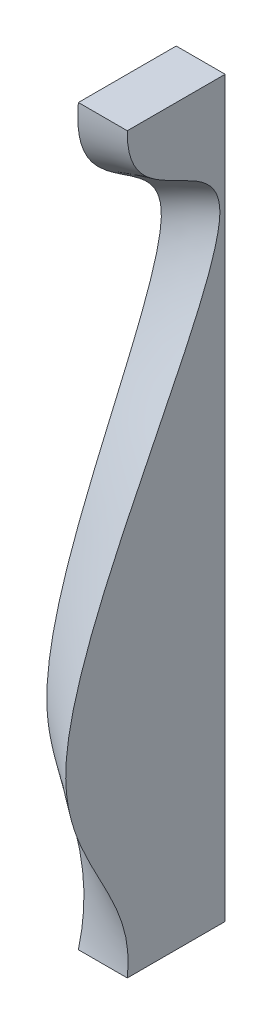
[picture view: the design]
ISO-10303-21;
HEADER;
FILE_DESCRIPTION(('STEP AP214'),'2;1');
FILE_NAME('part.step','',(''),(''),'','','');
FILE_SCHEMA(('AUTOMOTIVE_DESIGN { 1 0 10303 214 1 1 1 1 }'));
ENDSEC;
DATA;
#1=APPLICATION_CONTEXT('core data for automotive mechanical design processes');
#2=APPLICATION_PROTOCOL_DEFINITION('international standard','automotive_design',2000,#1);
#3=PRODUCT_CONTEXT('',#1,'mechanical');
#4=PRODUCT('Part','Part','',(#3));
#5=PRODUCT_RELATED_PRODUCT_CATEGORY('part','',(#4));
#6=PRODUCT_DEFINITION_FORMATION('','',#4);
#7=PRODUCT_DEFINITION_CONTEXT('part definition',#1,'design');
#8=PRODUCT_DEFINITION('design','',#6,#7);
#9=PRODUCT_DEFINITION_SHAPE('','',#8);
#10=(LENGTH_UNIT() NAMED_UNIT(*) SI_UNIT(.MILLI.,.METRE.));
#11=(NAMED_UNIT(*) PLANE_ANGLE_UNIT() SI_UNIT($,.RADIAN.));
#12=(NAMED_UNIT(*) SI_UNIT($,.STERADIAN.) SOLID_ANGLE_UNIT());
#13=UNCERTAINTY_MEASURE_WITH_UNIT(LENGTH_MEASURE(1.E-05),#10,'distance_accuracy_value','');
#14=(GEOMETRIC_REPRESENTATION_CONTEXT(3) GLOBAL_UNCERTAINTY_ASSIGNED_CONTEXT((#13)) GLOBAL_UNIT_ASSIGNED_CONTEXT((#10,
#11,#12)) REPRESENTATION_CONTEXT('',''));
#15=CARTESIAN_POINT('',(0.,0.,0.));
#16=DIRECTION('',(0.,0.,1.));
#17=DIRECTION('',(1.,0.,0.));
#18=AXIS2_PLACEMENT_3D('',#15,#16,#17);
#19=CARTESIAN_POINT('',(-250.,375.,253.120113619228));
#20=DIRECTION('',(1.,0.,0.));
#21=DIRECTION('',(0.,0.,-1.));
#22=AXIS2_PLACEMENT_3D('',#19,#20,#21);
#23=PLANE('',#22);
#24=CARTESIAN_POINT('',(-250.,375.,100.));
#25=CARTESIAN_POINT('',(-250.,374.213593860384,100.016067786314));
#26=CARTESIAN_POINT('',(-250.,373.426981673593,100.023402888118));
#27=CARTESIAN_POINT('',(-250.,371.851176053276,100.019526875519));
#28=CARTESIAN_POINT('',(-250.,371.061982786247,100.008253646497));
#29=CARTESIAN_POINT('',(-250.,369.482255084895,99.9659082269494));
#30=CARTESIAN_POINT('',(-250.,368.691721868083,99.9347894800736));
#31=CARTESIAN_POINT('',(-250.,367.110574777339,99.8514951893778));
#32=CARTESIAN_POINT('',(-250.,366.319962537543,99.7992883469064));
#33=CARTESIAN_POINT('',(-250.,364.739912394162,99.6725782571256));
#34=CARTESIAN_POINT('',(-250.,363.95047583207,99.5980581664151));
#35=CARTESIAN_POINT('',(-250.,362.374033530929,99.4255029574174));
#36=CARTESIAN_POINT('',(-250.,361.587028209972,99.3274640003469));
#37=CARTESIAN_POINT('',(-250.,360.011899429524,99.1060079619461));
#38=CARTESIAN_POINT('',(-250.,359.223796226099,98.9824461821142));
#39=CARTESIAN_POINT('',(-250.,357.652637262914,98.7091560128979));
#40=CARTESIAN_POINT('',(-250.,356.869578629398,98.5594442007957));
#41=CARTESIAN_POINT('',(-250.,355.309788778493,98.2327474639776));
#42=CARTESIAN_POINT('',(-250.,354.533053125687,98.0557837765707));
#43=CARTESIAN_POINT('',(-250.,352.9871734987,97.6735461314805));
#44=CARTESIAN_POINT('',(-250.,352.218024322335,97.4682932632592));
#45=CARTESIAN_POINT('',(-250.,350.688561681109,97.0285245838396));
#46=CARTESIAN_POINT('',(-250.,349.928243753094,96.7940243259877));
#47=CARTESIAN_POINT('',(-250.,348.417663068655,96.2949100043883));
#48=CARTESIAN_POINT('',(-250.,347.667398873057,96.0303003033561));
#49=CARTESIAN_POINT('',(-250.,346.17594428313,95.4694206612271));
#50=CARTESIAN_POINT('',(-250.,345.434792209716,95.1730486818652));
#51=CARTESIAN_POINT('',(-250.,343.965620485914,94.5489680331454));
#52=CARTESIAN_POINT('',(-250.,343.237603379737,94.2212533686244));
#53=CARTESIAN_POINT('',(-250.,341.796482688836,93.5344810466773));
#54=CARTESIAN_POINT('',(-250.,341.083379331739,93.1754229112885));
#55=CARTESIAN_POINT('',(-250.,339.673724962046,92.4262594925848));
#56=CARTESIAN_POINT('',(-250.,338.977172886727,92.0361562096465));
#57=CARTESIAN_POINT('',(-250.,337.605902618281,91.2277573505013));
#58=CARTESIAN_POINT('',(-250.,336.931083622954,90.8096327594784));
#59=CARTESIAN_POINT('',(-250.,335.600448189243,89.9441356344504));
#60=CARTESIAN_POINT('',(-250.,334.944632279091,89.4967622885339));
#61=CARTESIAN_POINT('',(-250.,333.653029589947,88.5739381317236));
#62=CARTESIAN_POINT('',(-250.,333.017243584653,88.0984862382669));
#63=CARTESIAN_POINT('',(-250.,331.766532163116,87.1209777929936));
#64=CARTESIAN_POINT('',(-250.,331.151605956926,86.6189222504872));
#65=CARTESIAN_POINT('',(-250.,329.795982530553,85.4645409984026));
#66=CARTESIAN_POINT('',(-250.,329.061096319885,84.8053794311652));
#67=CARTESIAN_POINT('',(-250.,327.624496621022,83.4516880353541));
#68=CARTESIAN_POINT('',(-250.,326.922789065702,82.7571519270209));
#69=CARTESIAN_POINT('',(-250.,325.552172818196,81.336255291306));
#70=CARTESIAN_POINT('',(-250.,324.883269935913,80.6098891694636));
#71=CARTESIAN_POINT('',(-250.,323.577339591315,79.1289408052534));
#72=CARTESIAN_POINT('',(-250.,322.940316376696,78.3743548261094));
#73=CARTESIAN_POINT('',(-250.,321.693944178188,76.8370718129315));
#74=CARTESIAN_POINT('',(-250.,321.084732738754,76.0542634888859));
#75=CARTESIAN_POINT('',(-250.,319.895088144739,74.4670304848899));
#76=CARTESIAN_POINT('',(-250.,319.314657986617,73.6626035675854));
#77=CARTESIAN_POINT('',(-250.,317.613524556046,71.2219711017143));
#78=CARTESIAN_POINT('',(-250.,316.532611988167,69.5579551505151));
#79=CARTESIAN_POINT('',(-250.,314.552458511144,66.3330919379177));
#80=CARTESIAN_POINT('',(-250.,313.645650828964,64.7768157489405));
#81=CARTESIAN_POINT('',(-250.,311.886408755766,61.633667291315));
#82=CARTESIAN_POINT('',(-250.,311.033983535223,60.0467899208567));
#83=CARTESIAN_POINT('',(-250.,309.366639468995,56.8532032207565));
#84=CARTESIAN_POINT('',(-250.,308.551728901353,55.2464896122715));
#85=CARTESIAN_POINT('',(-250.,306.941347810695,52.0209121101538));
#86=CARTESIAN_POINT('',(-250.,306.145903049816,50.4020354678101));
#87=CARTESIAN_POINT('',(-250.,304.557928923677,47.1634027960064));
#88=CARTESIAN_POINT('',(-250.,303.765398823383,45.5436471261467));
#89=CARTESIAN_POINT('',(-250.,302.564581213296,43.1200179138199));
#90=CARTESIAN_POINT('',(-250.,302.162320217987,42.3131723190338));
#91=CARTESIAN_POINT('',(-250.,301.35129905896,40.7027589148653));
#92=CARTESIAN_POINT('',(-250.,300.942538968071,39.8991910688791));
#93=CARTESIAN_POINT('',(-250.,300.072714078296,38.2129080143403));
#94=CARTESIAN_POINT('',(-250.,299.610650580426,37.3307061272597));
#95=CARTESIAN_POINT('',(-250.,298.671782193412,35.5740706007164));
#96=CARTESIAN_POINT('',(-250.,298.194976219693,34.6996375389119));
#97=CARTESIAN_POINT('',(-250.,297.222756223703,32.9609679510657));
#98=CARTESIAN_POINT('',(-250.,296.727339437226,32.0967329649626));
#99=CARTESIAN_POINT('',(-250.,295.713682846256,30.3810787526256));
#100=CARTESIAN_POINT('',(-250.,295.19543103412,29.5296665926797));
#101=CARTESIAN_POINT('',(-250.,294.13439560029,27.8471510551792));
#102=CARTESIAN_POINT('',(-250.,293.591723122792,27.0159778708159));
#103=CARTESIAN_POINT('',(-250.,292.475678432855,25.3744446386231));
#104=CARTESIAN_POINT('',(-250.,291.902307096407,24.5640839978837));
#105=CARTESIAN_POINT('',(-250.,290.721125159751,22.969581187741));
#106=CARTESIAN_POINT('',(-250.,290.113337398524,22.1854221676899));
#107=CARTESIAN_POINT('',(-250.,288.859407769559,20.6487944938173));
#108=CARTESIAN_POINT('',(-250.,288.213283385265,19.8963116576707));
#109=CARTESIAN_POINT('',(-250.,287.030826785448,18.5958745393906));
#110=CARTESIAN_POINT('',(-250.,286.502890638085,18.0402854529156));
#111=CARTESIAN_POINT('',(-250.,285.420994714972,16.9549699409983));
#112=CARTESIAN_POINT('',(-250.,284.867035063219,16.4252433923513));
#113=CARTESIAN_POINT('',(-250.,283.732500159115,15.3950518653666));
#114=CARTESIAN_POINT('',(-250.,283.151925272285,14.8945864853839));
#115=CARTESIAN_POINT('',(-250.,281.964767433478,13.9267974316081));
#116=CARTESIAN_POINT('',(-250.,281.358213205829,13.4594385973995));
#117=CARTESIAN_POINT('',(-250.,280.119112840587,12.5604108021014));
#118=CARTESIAN_POINT('',(-250.,279.486565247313,12.128743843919));
#119=CARTESIAN_POINT('',(-250.,278.19686599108,11.3039278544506));
#120=CARTESIAN_POINT('',(-250.,277.53971590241,10.9107763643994));
#121=CARTESIAN_POINT('',(-250.,276.199199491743,10.163182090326));
#122=CARTESIAN_POINT('',(-250.,275.51571335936,9.80895400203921));
#123=CARTESIAN_POINT('',(-250.,274.128256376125,9.14304308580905));
#124=CARTESIAN_POINT('',(-250.,273.42428383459,8.83136378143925));
#125=CARTESIAN_POINT('',(-250.,271.99883746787,8.25124842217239));
#126=CARTESIAN_POINT('',(-250.,271.277365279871,7.98280833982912));
#127=CARTESIAN_POINT('',(-250.,269.819489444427,7.48881330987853));
#128=CARTESIAN_POINT('',(-250.,269.083078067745,7.26328122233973));
#129=CARTESIAN_POINT('',(-250.,267.598637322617,6.85432617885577));
#130=CARTESIAN_POINT('',(-250.,266.850607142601,6.67090617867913));
#131=CARTESIAN_POINT('',(-250.,265.34571364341,6.34463144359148));
#132=CARTESIAN_POINT('',(-250.,264.588849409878,6.20178094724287));
#133=CARTESIAN_POINT('',(-250.,263.052791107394,5.95206179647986));
#134=CARTESIAN_POINT('',(-250.,262.273463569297,5.84601911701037));
#135=CARTESIAN_POINT('',(-250.,260.710465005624,5.67173985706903));
#136=CARTESIAN_POINT('',(-250.,259.9267930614,5.60351160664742));
#137=CARTESIAN_POINT('',(-250.,258.356999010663,5.50230729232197));
#138=CARTESIAN_POINT('',(-250.,257.570876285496,5.46934100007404));
#139=CARTESIAN_POINT('',(-250.,255.9980731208,5.43607383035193));
#140=CARTESIAN_POINT('',(-250.,255.211392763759,5.43576884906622));
#141=CARTESIAN_POINT('',(-250.,253.635574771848,5.46537979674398));
#142=CARTESIAN_POINT('',(-250.,252.846439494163,5.49541338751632));
#143=CARTESIAN_POINT('',(-250.,251.269881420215,5.58233007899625));
#144=CARTESIAN_POINT('',(-250.,250.482458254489,5.63920665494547));
#145=CARTESIAN_POINT('',(-250.,248.909704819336,5.77670104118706));
#146=CARTESIAN_POINT('',(-250.,248.12437457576,5.85731914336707));
#147=CARTESIAN_POINT('',(-250.,246.55623892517,6.03966594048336));
#148=CARTESIAN_POINT('',(-250.,245.773433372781,6.14139339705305));
#149=CARTESIAN_POINT('',(-250.,244.104251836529,6.37882046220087));
#150=CARTESIAN_POINT('',(-250.,243.218266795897,6.51725860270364));
#151=CARTESIAN_POINT('',(-250.,241.449902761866,6.81566334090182));
#152=CARTESIAN_POINT('',(-250.,240.567523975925,6.97563115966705));
#153=CARTESIAN_POINT('',(-250.,238.806163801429,7.31477367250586));
#154=CARTESIAN_POINT('',(-250.,237.927183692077,7.49395498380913));
#155=CARTESIAN_POINT('',(-250.,236.172918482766,7.86944897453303));
#156=CARTESIAN_POINT('',(-250.,235.297633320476,8.06576136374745));
#157=CARTESIAN_POINT('',(-250.,233.549648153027,8.47402145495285));
#158=CARTESIAN_POINT('',(-250.,232.676952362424,8.68598715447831));
#159=CARTESIAN_POINT('',(-250.,230.935066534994,9.1238486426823));
#160=CARTESIAN_POINT('',(-250.,230.065876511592,9.34974448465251));
#161=CARTESIAN_POINT('',(-250.,228.329923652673,9.81441706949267));
#162=CARTESIAN_POINT('',(-250.,227.46316455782,10.0532077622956));
#163=CARTESIAN_POINT('',(-250.,225.732893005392,10.5423026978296));
#164=CARTESIAN_POINT('',(-250.,224.86938059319,10.7926071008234));
#165=CARTESIAN_POINT('',(-250.,223.144979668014,11.3038689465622));
#166=CARTESIAN_POINT('',(-250.,222.284092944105,11.5648324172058));
#167=CARTESIAN_POINT('',(-250.,220.565297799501,12.096399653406));
#168=CARTESIAN_POINT('',(-250.,219.707389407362,12.3670035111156));
#169=CARTESIAN_POINT('',(-250.,217.138331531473,13.1919657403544));
#170=CARTESIAN_POINT('',(-250.,215.431434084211,13.7595987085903));
#171=CARTESIAN_POINT('',(-250.,212.017417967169,14.928639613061));
#172=CARTESIAN_POINT('',(-250.,210.310364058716,15.5302357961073));
#173=CARTESIAN_POINT('',(-250.,206.907527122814,16.7590627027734));
#174=CARTESIAN_POINT('',(-250.,205.211734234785,17.3862661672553));
#175=CARTESIAN_POINT('',(-250.,201.829958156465,18.6629462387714));
#176=CARTESIAN_POINT('',(-250.,200.143968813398,19.3124065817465));
#177=CARTESIAN_POINT('',(-250.,196.780557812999,20.630828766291));
#178=CARTESIAN_POINT('',(-250.,195.103132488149,21.2997812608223));
#179=CARTESIAN_POINT('',(-250.,192.592519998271,22.3161454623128));
#180=CARTESIAN_POINT('',(-250.,191.756686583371,22.6570408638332));
#181=CARTESIAN_POINT('',(-250.,190.086694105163,23.3429119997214));
#182=CARTESIAN_POINT('',(-250.,189.252535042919,23.687887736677));
#183=CARTESIAN_POINT('',(-250.,187.58592056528,24.3816247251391));
#184=CARTESIAN_POINT('',(-250.,186.753464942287,24.7303854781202));
#185=CARTESIAN_POINT('',(-250.,185.090074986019,25.4315073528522));
#186=CARTESIAN_POINT('',(-250.,184.259140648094,25.7838684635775));
#187=CARTESIAN_POINT('',(-250.,181.797675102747,26.8335904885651));
#188=CARTESIAN_POINT('',(-250.,180.169207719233,27.5357954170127));
#189=CARTESIAN_POINT('',(-250.,176.917326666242,28.9518221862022));
#190=CARTESIAN_POINT('',(-250.,175.293913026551,29.6656440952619));
#191=CARTESIAN_POINT('',(-250.,172.051586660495,31.1036699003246));
#192=CARTESIAN_POINT('',(-250.,170.432674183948,31.8278743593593));
#193=CARTESIAN_POINT('',(-250.,167.199006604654,33.2855104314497));
#194=CARTESIAN_POINT('',(-250.,165.58425151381,34.0189420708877));
#195=CARTESIAN_POINT('',(-250.,160.745401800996,36.2316499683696));
#196=CARTESIAN_POINT('',(-250.,157.526936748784,37.7232439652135));
#197=CARTESIAN_POINT('',(-250.,151.102189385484,40.7324582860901));
#198=CARTESIAN_POINT('',(-250.,147.895907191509,42.2500788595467));
#199=CARTESIAN_POINT('',(-250.,141.489736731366,45.3074006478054));
#200=CARTESIAN_POINT('',(-250.,138.289858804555,46.8471235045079));
#201=CARTESIAN_POINT('',(-250.,131.897940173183,49.9422902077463));
#202=CARTESIAN_POINT('',(-250.,128.705899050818,51.4977331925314));
#203=CARTESIAN_POINT('',(-250.,122.327650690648,54.6203474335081));
#204=CARTESIAN_POINT('',(-250.,119.141443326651,56.1875184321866));
#205=CARTESIAN_POINT('',(-250.,112.773091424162,59.3300653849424));
#206=CARTESIAN_POINT('',(-250.,109.590946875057,60.9054413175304));
#207=CARTESIAN_POINT('',(-250.,103.226673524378,64.0624449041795));
#208=CARTESIAN_POINT('',(-250.,100.044546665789,65.6440764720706));
#209=CARTESIAN_POINT('',(-250.,93.6813167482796,68.8094607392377));
#210=CARTESIAN_POINT('',(-250.,90.5002136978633,70.3932134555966));
#211=CARTESIAN_POINT('',(-250.,84.137680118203,73.5601113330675));
#212=CARTESIAN_POINT('',(-250.,80.9562495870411,75.1432564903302));
#213=CARTESIAN_POINT('',(-250.,74.5917780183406,78.3063460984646));
#214=CARTESIAN_POINT('',(-250.,71.4087369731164,79.8862905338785));
#215=CARTESIAN_POINT('',(-250.,63.9929354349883,83.5589264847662));
#216=CARTESIAN_POINT('',(-250.,59.75908987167,85.6494296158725));
#217=CARTESIAN_POINT('',(-250.,51.2836060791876,89.8145359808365));
#218=CARTESIAN_POINT('',(-250.,47.0419678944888,91.8891393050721));
#219=CARTESIAN_POINT('',(-250.,38.5481354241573,96.0166037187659));
#220=CARTESIAN_POINT('',(-250.,34.2959411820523,98.069464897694));
#221=CARTESIAN_POINT('',(-250.,25.7811124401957,102.146001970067));
#222=CARTESIAN_POINT('',(-250.,21.518486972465,104.169696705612));
#223=CARTESIAN_POINT('',(-250.,12.977108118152,108.182886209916));
#224=CARTESIAN_POINT('',(-250.,8.69835461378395,110.172380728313));
#225=CARTESIAN_POINT('',(-250.,0.121736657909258,114.11019478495));
#226=CARTESIAN_POINT('',(-250.,-4.17612843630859,116.058512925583));
#227=CARTESIAN_POINT('',(-250.,-12.7913387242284,119.904971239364));
#228=CARTESIAN_POINT('',(-250.,-17.1086713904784,121.803139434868));
#229=CARTESIAN_POINT('',(-250.,-25.7682883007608,125.54155376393));
#230=CARTESIAN_POINT('',(-250.,-30.1105718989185,127.381801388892));
#231=CARTESIAN_POINT('',(-250.,-36.645057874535,130.090936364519));
#232=CARTESIAN_POINT('',(-250.,-38.8266667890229,130.985416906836));
#233=CARTESIAN_POINT('',(-250.,-43.1973848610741,132.755848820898));
#234=CARTESIAN_POINT('',(-250.,-45.3864939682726,133.631800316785));
#235=CARTESIAN_POINT('',(-250.,-48.9765989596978,135.049287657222));
#236=CARTESIAN_POINT('',(-250.,-50.3752376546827,135.596798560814));
#237=CARTESIAN_POINT('',(-250.,-53.1758494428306,136.683213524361));
#238=CARTESIAN_POINT('',(-250.,-54.5778225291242,137.222117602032));
#239=CARTESIAN_POINT('',(-250.,-58.7891943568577,138.825333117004));
#240=CARTESIAN_POINT('',(-250.,-61.6037892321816,139.876046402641));
#241=CARTESIAN_POINT('',(-250.,-67.2479573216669,141.937175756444));
#242=CARTESIAN_POINT('',(-250.,-70.0775316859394,142.947588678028));
#243=CARTESIAN_POINT('',(-250.,-75.752753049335,144.923464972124));
#244=CARTESIAN_POINT('',(-250.,-78.5984019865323,145.888922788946));
#245=CARTESIAN_POINT('',(-250.,-84.3070787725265,147.769605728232));
#246=CARTESIAN_POINT('',(-250.,-87.1701108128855,148.68481815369));
#247=CARTESIAN_POINT('',(-250.,-92.9060745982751,150.456145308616));
#248=CARTESIAN_POINT('',(-250.,-95.7789594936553,151.312411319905));
#249=CARTESIAN_POINT('',(-250.,-101.543128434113,152.961337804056));
#250=CARTESIAN_POINT('',(-250.,-104.434413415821,153.753995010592));
#251=CARTESIAN_POINT('',(-250.,-110.235452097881,155.267085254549));
#252=CARTESIAN_POINT('',(-250.,-113.14520272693,155.987529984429));
#253=CARTESIAN_POINT('',(-250.,-117.523923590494,157.006492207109));
#254=CARTESIAN_POINT('',(-250.,-118.985757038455,157.335843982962));
#255=CARTESIAN_POINT('',(-250.,-121.914209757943,157.972551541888));
#256=CARTESIAN_POINT('',(-250.,-123.380828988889,158.279907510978));
#257=CARTESIAN_POINT('',(-250.,-126.319056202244,158.871110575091));
#258=CARTESIAN_POINT('',(-250.,-127.790664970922,159.154953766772));
#259=CARTESIAN_POINT('',(-250.,-130.738595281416,159.697363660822));
#260=CARTESIAN_POINT('',(-250.,-132.214916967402,159.955929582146));
#261=CARTESIAN_POINT('',(-250.,-134.905530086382,160.401720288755));
#262=CARTESIAN_POINT('',(-250.,-136.119083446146,160.593403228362));
#263=CARTESIAN_POINT('',(-250.,-138.549114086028,160.957369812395));
#264=CARTESIAN_POINT('',(-250.,-139.765591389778,161.129653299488));
#265=CARTESIAN_POINT('',(-250.,-142.201383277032,161.453602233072));
#266=CARTESIAN_POINT('',(-250.,-143.420698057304,161.605266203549));
#267=CARTESIAN_POINT('',(-250.,-145.861864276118,161.886630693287));
#268=CARTESIAN_POINT('',(-250.,-147.083715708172,162.016331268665));
#269=CARTESIAN_POINT('',(-250.,-149.529041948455,162.252264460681));
#270=CARTESIAN_POINT('',(-250.,-150.75251556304,162.358509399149));
#271=CARTESIAN_POINT('',(-250.,-153.201390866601,162.546063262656));
#272=CARTESIAN_POINT('',(-250.,-154.426792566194,162.627372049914));
#273=CARTESIAN_POINT('',(-250.,-156.878901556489,162.763338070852));
#274=CARTESIAN_POINT('',(-250.,-158.105608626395,162.817999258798));
#275=CARTESIAN_POINT('',(-250.,-160.559940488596,162.89891866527));
#276=CARTESIAN_POINT('',(-250.,-161.787565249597,162.925177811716));
#277=CARTESIAN_POINT('',(-250.,-163.571207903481,162.942530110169));
#278=CARTESIAN_POINT('',(-250.,-164.127135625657,162.945003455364));
#279=CARTESIAN_POINT('',(-250.,-165.238980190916,162.944061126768));
#280=CARTESIAN_POINT('',(-250.,-165.79489703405,162.940645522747));
#281=CARTESIAN_POINT('',(-250.,-167.462524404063,162.921546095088));
#282=CARTESIAN_POINT('',(-250.,-168.574145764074,162.897009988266));
#283=CARTESIAN_POINT('',(-250.,-170.796996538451,162.824279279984));
#284=CARTESIAN_POINT('',(-250.,-171.908225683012,162.776076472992));
#285=CARTESIAN_POINT('',(-250.,-174.129398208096,162.656090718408));
#286=CARTESIAN_POINT('',(-250.,-175.239341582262,162.584307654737));
#287=CARTESIAN_POINT('',(-250.,-178.566802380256,162.33371239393));
#288=CARTESIAN_POINT('',(-250.,-180.781772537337,162.11965997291));
#289=CARTESIAN_POINT('',(-250.,-185.200444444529,161.598460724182));
#290=CARTESIAN_POINT('',(-250.,-187.404147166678,161.29132206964));
#291=CARTESIAN_POINT('',(-250.,-191.798597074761,160.585832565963));
#292=CARTESIAN_POINT('',(-250.,-193.989333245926,160.187413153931));
#293=CARTESIAN_POINT('',(-250.,-198.352815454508,159.302851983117));
#294=CARTESIAN_POINT('',(-250.,-200.525562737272,158.816716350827));
#295=CARTESIAN_POINT('',(-250.,-204.850690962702,157.761108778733));
#296=CARTESIAN_POINT('',(-250.,-207.003071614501,157.191635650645));
#297=CARTESIAN_POINT('',(-250.,-211.285362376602,155.974741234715));
#298=CARTESIAN_POINT('',(-250.,-213.415275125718,155.327329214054));
#299=CARTESIAN_POINT('',(-250.,-217.177215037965,154.113688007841));
#300=CARTESIAN_POINT('',(-250.,-218.813885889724,153.56176398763));
#301=CARTESIAN_POINT('',(-250.,-222.073138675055,152.417646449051));
#302=CARTESIAN_POINT('',(-250.,-223.695720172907,151.825451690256));
#303=CARTESIAN_POINT('',(-250.,-226.927054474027,150.603945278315));
#304=CARTESIAN_POINT('',(-250.,-228.535805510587,149.974628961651));
#305=CARTESIAN_POINT('',(-250.,-231.739732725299,148.68225245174));
#306=CARTESIAN_POINT('',(-250.,-233.334908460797,148.019191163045));
#307=CARTESIAN_POINT('',(-250.,-236.512352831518,146.662729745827));
#308=CARTESIAN_POINT('',(-250.,-238.094620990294,145.969328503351));
#309=CARTESIAN_POINT('',(-250.,-241.247136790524,144.555665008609));
#310=CARTESIAN_POINT('',(-250.,-242.817384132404,143.83540208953));
#311=CARTESIAN_POINT('',(-250.,-245.95298615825,142.368728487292));
#312=CARTESIAN_POINT('',(-250.,-247.518298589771,141.62222764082));
#313=CARTESIAN_POINT('',(-250.,-250.639278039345,140.109318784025));
#314=CARTESIAN_POINT('',(-250.,-252.194944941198,139.342910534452));
#315=CARTESIAN_POINT('',(-250.,-255.297868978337,137.79399053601));
#316=CARTESIAN_POINT('',(-250.,-256.845127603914,137.011481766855));
#317=CARTESIAN_POINT('',(-250.,-259.933229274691,135.433933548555));
#318=CARTESIAN_POINT('',(-250.,-261.474072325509,134.638894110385));
#319=CARTESIAN_POINT('',(-250.,-264.551186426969,133.040072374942));
#320=CARTESIAN_POINT('',(-250.,-266.087457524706,132.236290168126));
#321=CARTESIAN_POINT('',(-250.,-269.157435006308,130.623853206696));
#322=CARTESIAN_POINT('',(-250.,-270.69114139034,129.815198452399));
#323=CARTESIAN_POINT('',(-250.,-274.477139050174,127.81760739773));
#324=CARTESIAN_POINT('',(-250.,-276.72915826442,126.628156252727));
#325=CARTESIAN_POINT('',(-250.,-281.239056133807,124.260625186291));
#326=CARTESIAN_POINT('',(-250.,-283.496934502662,123.082544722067));
#327=CARTESIAN_POINT('',(-250.,-288.026138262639,120.751695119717));
#328=CARTESIAN_POINT('',(-250.,-290.297465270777,119.598929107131));
#329=CARTESIAN_POINT('',(-250.,-294.8615962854,117.333502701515));
#330=CARTESIAN_POINT('',(-250.,-297.154410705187,116.220863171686));
#331=CARTESIAN_POINT('',(-250.,-301.755308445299,114.058318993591));
#332=CARTESIAN_POINT('',(-250.,-304.063253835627,113.008122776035));
#333=CARTESIAN_POINT('',(-250.,-308.711518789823,110.981806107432));
#334=CARTESIAN_POINT('',(-250.,-311.051837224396,110.005683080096));
#335=CARTESIAN_POINT('',(-250.,-315.767850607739,108.146420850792));
#336=CARTESIAN_POINT('',(-250.,-318.143522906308,107.263224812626));
#337=CARTESIAN_POINT('',(-250.,-321.735429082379,106.022003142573));
#338=CARTESIAN_POINT('',(-250.,-322.937312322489,105.622235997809));
#339=CARTESIAN_POINT('',(-250.,-325.350658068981,104.852809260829));
#340=CARTESIAN_POINT('',(-250.,-326.562120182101,104.483148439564));
#341=CARTESIAN_POINT('',(-250.,-329.058524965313,103.75756826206));
#342=CARTESIAN_POINT('',(-250.,-330.343977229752,103.403398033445));
#343=CARTESIAN_POINT('',(-250.,-332.925100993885,102.733361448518));
#344=CARTESIAN_POINT('',(-250.,-334.220774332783,102.417502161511));
#345=CARTESIAN_POINT('',(-250.,-336.821428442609,101.826475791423));
#346=CARTESIAN_POINT('',(-250.,-338.126409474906,101.551309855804));
#347=CARTESIAN_POINT('',(-250.,-340.744699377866,101.043748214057));
#348=CARTESIAN_POINT('',(-250.,-342.058008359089,100.811353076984));
#349=CARTESIAN_POINT('',(-250.,-344.691903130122,100.391075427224));
#350=CARTESIAN_POINT('',(-250.,-346.012489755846,100.203198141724));
#351=CARTESIAN_POINT('',(-250.,-348.65781866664,99.8735923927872));
#352=CARTESIAN_POINT('',(-250.,-349.982554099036,99.7318090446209));
#353=CARTESIAN_POINT('',(-250.,-352.636376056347,99.4950719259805));
#354=CARTESIAN_POINT('',(-250.,-353.965463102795,99.4001239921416));
#355=CARTESIAN_POINT('',(-250.,-356.626034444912,99.2576757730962));
#356=CARTESIAN_POINT('',(-250.,-357.957518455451,99.2101701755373));
#357=CARTESIAN_POINT('',(-250.,-360.620894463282,99.1627520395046));
#358=CARTESIAN_POINT('',(-250.,-361.952786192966,99.1628242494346));
#359=CARTESIAN_POINT('',(-250.,-364.615039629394,99.2102607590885));
#360=CARTESIAN_POINT('',(-250.,-365.9454017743,99.2575993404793));
#361=CARTESIAN_POINT('',(-250.,-367.704971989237,99.3511181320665));
#362=CARTESIAN_POINT('',(-250.,-368.135362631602,99.3764450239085));
#363=CARTESIAN_POINT('',(-250.,-368.995766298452,99.4319526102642));
#364=CARTESIAN_POINT('',(-250.,-369.425779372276,99.4621325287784));
#365=CARTESIAN_POINT('',(-250.,-370.285404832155,99.5273139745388));
#366=CARTESIAN_POINT('',(-250.,-370.715017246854,99.5623151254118));
#367=CARTESIAN_POINT('',(-250.,-371.573474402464,99.6370736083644));
#368=CARTESIAN_POINT('',(-250.,-372.002319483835,99.6768270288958));
#369=CARTESIAN_POINT('',(-250.,-372.859576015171,99.7610765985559));
#370=CARTESIAN_POINT('',(-250.,-373.287987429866,99.8055731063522));
#371=CARTESIAN_POINT('',(-250.,-374.144359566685,99.8992700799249));
#372=CARTESIAN_POINT('',(-250.,-374.572320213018,99.9484712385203));
#373=CARTESIAN_POINT('',(-250.,-375.,100.));
#374=B_SPLINE_CURVE_WITH_KNOTS('',3,(#24,#25,#26,#27,#28,#29,#30,#31,#32,#33,#34,#35,#36,#37,
#38,#39,#40,#41,#42,#43,#44,#45,#46,#47,#48,#49,#50,#51,#52,#53,#54,#55,#56,#57,#58,#59,#60,#61,
#62,#63,#64,#65,#66,#67,#68,#69,#70,#71,#72,#73,#74,#75,#76,#77,#78,#79,#80,#81,#82,#83,#84,#85,
#86,#87,#88,#89,#90,#91,#92,#93,#94,#95,#96,#97,#98,#99,#100,#101,#102,#103,#104,#105,#106,#107,
#108,#109,#110,#111,#112,#113,#114,#115,#116,#117,#118,#119,#120,#121,#122,#123,#124,#125,#126,
#127,#128,#129,#130,#131,#132,#133,#134,#135,#136,#137,#138,#139,#140,#141,#142,#143,#144,#145,
#146,#147,#148,#149,#150,#151,#152,#153,#154,#155,#156,#157,#158,#159,#160,#161,#162,#163,#164,
#165,#166,#167,#168,#169,#170,#171,#172,#173,#174,#175,#176,#177,#178,#179,#180,#181,#182,#183,
#184,#185,#186,#187,#188,#189,#190,#191,#192,#193,#194,#195,#196,#197,#198,#199,#200,#201,#202,
#203,#204,#205,#206,#207,#208,#209,#210,#211,#212,#213,#214,#215,#216,#217,#218,#219,#220,#221,
#222,#223,#224,#225,#226,#227,#228,#229,#230,#231,#232,#233,#234,#235,#236,#237,#238,#239,#240,
#241,#242,#243,#244,#245,#246,#247,#248,#249,#250,#251,#252,#253,#254,#255,#256,#257,#258,#259,
#260,#261,#262,#263,#264,#265,#266,#267,#268,#269,#270,#271,#272,#273,#274,#275,#276,#277,#278,
#279,#280,#281,#282,#283,#284,#285,#286,#287,#288,#289,#290,#291,#292,#293,#294,#295,#296,#297,
#298,#299,#300,#301,#302,#303,#304,#305,#306,#307,#308,#309,#310,#311,#312,#313,#314,#315,#316,
#317,#318,#319,#320,#321,#322,#323,#324,#325,#326,#327,#328,#329,#330,#331,#332,#333,#334,#335,
#336,#337,#338,#339,#340,#341,#342,#343,#344,#345,#346,#347,#348,#349,#350,#351,#352,#353,#354,
#355,#356,#357,#358,#359,#360,#361,#362,#363,#364,#365,#366,#367,#368,#369,#370,#371,#372,#373),
.UNSPECIFIED.,.F.,.F.,(4,2,2,2,2,2,2,2,2,2,2,2,2,2,2,2,2,2,2,2,2,2,2,2,2,2,2,2,2,2,2,2,2,2,2,2,
2,2,2,2,2,2,2,2,2,2,2,2,2,2,2,2,2,2,2,2,2,2,2,2,2,2,2,2,2,2,2,2,2,2,2,2,2,2,2,2,2,2,2,2,2,2,2,2,
2,2,2,2,2,2,2,2,2,2,2,2,2,2,2,2,2,2,2,2,2,2,2,2,2,2,2,2,2,2,2,2,2,2,2,2,2,2,2,2,2,2,2,2,2,2,2,2,
2,2,2,2,2,2,2,2,2,2,2,2,2,2,2,2,2,2,2,2,2,2,2,2,2,2,2,2,2,2,2,2,2,2,2,2,2,2,2,2,2,2,4),(0.,
2.35970332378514,4.72729927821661,7.1004699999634,9.4771759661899,11.855680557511,
14.2345736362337,16.6273431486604,19.0186012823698,21.4080052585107,23.7956374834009,
26.182005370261,28.5680279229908,30.9619595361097,33.3563499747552,35.7507769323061,
38.1450497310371,40.5258503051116,42.9067169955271,45.2876755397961,47.6685438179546,
50.6288229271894,53.5896293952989,56.5509583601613,59.5126808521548,62.4877409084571,
65.4631100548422,71.4120909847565,76.8144003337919,82.2176182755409,87.6220228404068,
93.0332303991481,98.4429641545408,101.147628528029,103.852262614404,106.839806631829,
109.827570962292,112.815780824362,115.805581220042,118.782931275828,121.760196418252,
124.735508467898,127.709473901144,130.007948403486,132.306411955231,134.60484395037,
136.900797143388,139.196879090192,141.492814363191,143.800837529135,146.109051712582,
148.417050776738,150.726276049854,153.035663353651,155.345291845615,157.703827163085,
160.062881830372,162.422590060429,164.782001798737,167.150599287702,169.518621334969,
171.886672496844,174.254584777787,176.944484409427,179.634536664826,182.325518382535,
185.016454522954,187.710534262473,190.404624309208,193.101689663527,195.79879257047,
198.497442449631,201.19611813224,206.592169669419,212.021810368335,217.445814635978,
222.86593649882,228.283500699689,230.991525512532,233.699552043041,236.407226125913,
239.114891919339,244.435077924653,249.755295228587,255.07580214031,260.396324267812,
271.038071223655,281.679920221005,292.333016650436,302.985532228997,313.637814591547,
324.290069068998,334.950620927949,345.611259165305,356.271963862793,366.93271992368,
381.098179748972,395.263558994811,409.428879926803,423.584597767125,437.74041919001,
451.896720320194,466.044936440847,480.192787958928,487.266306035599,494.339776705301,
498.845704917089,503.351623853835,512.364288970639,521.377656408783,530.392134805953,
539.408880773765,548.401549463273,557.394679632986,566.386351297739,570.881640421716,
575.376891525,579.872887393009,584.369022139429,588.054674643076,591.740357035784,595.426303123,
599.112239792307,602.796235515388,606.480251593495,610.163720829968,613.847069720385,
615.514843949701,617.182598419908,620.518005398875,623.854569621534,627.19115026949,
633.864845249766,640.537954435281,647.216092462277,653.893764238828,660.571531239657,
667.24850501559,672.429658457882,677.610971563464,682.792936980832,687.975070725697,
693.157394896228,698.339847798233,703.542296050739,708.744806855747,713.946363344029,
719.147915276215,724.349413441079,729.550911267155,737.191425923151,744.83157402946,
752.472660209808,760.117663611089,767.723593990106,775.329259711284,782.930246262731,
786.729791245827,790.529181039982,794.528675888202,798.528907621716,802.529252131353,
806.529649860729,810.530517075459,814.526602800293,818.523186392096,822.519322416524,
826.514177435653,830.506859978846,831.800248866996,833.093431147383,834.386512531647,
835.678536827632,836.970658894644,838.262971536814),.UNSPECIFIED.);
#375=CARTESIAN_POINT('',(-250.,375.,100.));
#376=VERTEX_POINT('',#375);
#377=CARTESIAN_POINT('',(-250.,-375.,100.));
#378=VERTEX_POINT('',#377);
#379=EDGE_CURVE('E88',#376,#378,#374,.T.);
#380=ORIENTED_EDGE('',*,*,#379,.T.);
#381=DIRECTION('',(0.,0.,-1.));
#382=VECTOR('',#381,1.);
#383=CARTESIAN_POINT('',(-250.,-375.,253.120113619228));
#384=LINE('',#383,#382);
#385=CARTESIAN_POINT('',(-250.,-375.,0.));
#386=VERTEX_POINT('',#385);
#387=EDGE_CURVE('E50',#378,#386,#384,.T.);
#388=ORIENTED_EDGE('',*,*,#387,.T.);
#389=DIRECTION('',(0.,-1.,0.));
#390=VECTOR('',#389,1.);
#391=CARTESIAN_POINT('',(-250.,375.,0.));
#392=LINE('',#391,#390);
#393=CARTESIAN_POINT('',(-250.,375.,0.));
#394=VERTEX_POINT('',#393);
#395=EDGE_CURVE('E87',#394,#386,#392,.T.);
#396=ORIENTED_EDGE('',*,*,#395,.F.);
#397=DIRECTION('',(0.,0.,-1.));
#398=VECTOR('',#397,1.);
#399=CARTESIAN_POINT('',(-250.,375.,253.120113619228));
#400=LINE('',#399,#398);
#401=EDGE_CURVE('E65',#376,#394,#400,.T.);
#402=ORIENTED_EDGE('',*,*,#401,.F.);
#403=EDGE_LOOP('',(#380,#388,#396,#402));
#404=FACE_BOUND('',#403,.T.);
#405=ADVANCED_FACE('F35',(#404),#23,.T.);
#406=CARTESIAN_POINT('',(0.,0.,0.));
#407=DIRECTION('',(0.,0.,-1.));
#408=DIRECTION('',(-1.,0.,0.));
#409=AXIS2_PLACEMENT_3D('',#406,#407,#408);
#410=PLANE('',#409);
#411=DIRECTION('',(1.,0.,0.));
#412=VECTOR('',#411,1.);
#413=CARTESIAN_POINT('',(-750.,-375.,0.));
#414=LINE('',#413,#412);
#415=CARTESIAN_POINT('',(-300.,-375.,0.));
#416=VERTEX_POINT('',#415);
#417=EDGE_CURVE('E79',#416,#386,#414,.T.);
#418=ORIENTED_EDGE('',*,*,#417,.F.);
#419=DIRECTION('',(0.,1.,0.));
#420=VECTOR('',#419,1.);
#421=CARTESIAN_POINT('',(-300.,375.,0.));
#422=LINE('',#421,#420);
#423=CARTESIAN_POINT('',(-300.,375.,0.));
#424=VERTEX_POINT('',#423);
#425=EDGE_CURVE('E157',#416,#424,#422,.T.);
#426=ORIENTED_EDGE('',*,*,#425,.T.);
#427=DIRECTION('',(-1.,0.,0.));
#428=VECTOR('',#427,1.);
#429=CARTESIAN_POINT('',(-750.,375.,0.));
#430=LINE('',#429,#428);
#431=EDGE_CURVE('E93',#394,#424,#430,.T.);
#432=ORIENTED_EDGE('',*,*,#431,.F.);
#433=ORIENTED_EDGE('',*,*,#395,.T.);
#434=EDGE_LOOP('',(#418,#426,#432,#433));
#435=FACE_BOUND('',#434,.T.);
#436=ADVANCED_FACE('F91',(#435),#410,.T.);
#437=CARTESIAN_POINT('',(750.,-375.,100.));
#438=CARTESIAN_POINT('',(750.,-302.078506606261,100.));
#439=CARTESIAN_POINT('',(750.,-224.483786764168,100.));
#440=CARTESIAN_POINT('',(750.,-61.5160152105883,100.));
#441=CARTESIAN_POINT('',(750.,39.4445673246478,100.));
#442=CARTESIAN_POINT('',(750.,211.849847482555,100.));
#443=CARTESIAN_POINT('',(750.,298.882075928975,100.));
#444=CARTESIAN_POINT('',(750.,375.,100.));
#445=CARTESIAN_POINT('',(669.085175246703,-375.,100.));
#446=CARTESIAN_POINT('',(669.085175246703,-302.078506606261,100.));
#447=CARTESIAN_POINT('',(669.085175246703,-234.282472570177,121.198481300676));
#448=CARTESIAN_POINT('',(669.085175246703,-62.2283080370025,120.288550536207));
#449=CARTESIAN_POINT('',(669.085175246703,68.0647781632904,82.7868169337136));
#450=CARTESIAN_POINT('',(669.085175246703,240.312514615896,73.0426687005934));
#451=CARTESIAN_POINT('',(669.085175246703,298.882075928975,100.));
#452=CARTESIAN_POINT('',(669.085175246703,375.,100.));
#453=CARTESIAN_POINT('',(500.445116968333,-375.,100.));
#454=CARTESIAN_POINT('',(517.991528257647,-284.627602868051,95.5040591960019));
#455=CARTESIAN_POINT('',(530.038001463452,-221.673003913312,150.719602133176));
#456=CARTESIAN_POINT('',(473.74510655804,-71.7416270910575,167.060530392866));
#457=CARTESIAN_POINT('',(387.213321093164,45.6135081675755,91.591323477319));
#458=CARTESIAN_POINT('',(378.694107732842,207.638743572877,66.6461848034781));
#459=CARTESIAN_POINT('',(433.17831170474,253.396603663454,122.492891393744));
#460=CARTESIAN_POINT('',(500.445116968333,375.,100.));
#461=CARTESIAN_POINT('',(285.091607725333,-375.,100.));
#462=CARTESIAN_POINT('',(309.270321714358,-264.297524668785,86.4064578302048));
#463=CARTESIAN_POINT('',(325.856840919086,-200.08226970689,164.07204721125));
#464=CARTESIAN_POINT('',(247.47112957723,-80.9425320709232,234.992870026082));
#465=CARTESIAN_POINT('',(127.240382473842,2.40271344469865,186.756001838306));
#466=CARTESIAN_POINT('',(115.567806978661,152.518027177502,151.057444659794));
#467=CARTESIAN_POINT('',(191.428893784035,202.025100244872,189.039851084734));
#468=CARTESIAN_POINT('',(285.091607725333,375.,100.));
#469=CARTESIAN_POINT('',(47.4554331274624,-375.,100.));
#470=CARTESIAN_POINT('',(51.0669239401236,-278.639867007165,99.5141662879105));
#471=CARTESIAN_POINT('',(52.9210710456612,-231.452124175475,201.325948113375));
#472=CARTESIAN_POINT('',(3.18149891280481,-90.8615864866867,272.445475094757));
#473=CARTESIAN_POINT('',(-61.0346058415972,45.7948958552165,186.157760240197));
#474=CARTESIAN_POINT('',(-59.6612105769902,205.286893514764,133.941969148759));
#475=CARTESIAN_POINT('',(-11.8049718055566,220.40073671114,189.8209162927));
#476=CARTESIAN_POINT('',(47.4554331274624,375.,100.));
#477=CARTESIAN_POINT('',(-175.903454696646,-375.,100.));
#478=CARTESIAN_POINT('',(-199.823715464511,-320.588060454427,126.731848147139));
#479=CARTESIAN_POINT('',(-216.967937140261,-300.821135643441,242.921959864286));
#480=CARTESIAN_POINT('',(-184.265304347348,-55.1410097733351,206.147478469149));
#481=CARTESIAN_POINT('',(-119.865061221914,249.096629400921,-32.5779079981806));
#482=CARTESIAN_POINT('',(-104.641938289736,431.262460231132,-94.4845569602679));
#483=CARTESIAN_POINT('',(-136.623034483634,348.137040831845,60.785640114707));
#484=CARTESIAN_POINT('',(-175.903454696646,375.,100.));
#485=CARTESIAN_POINT('',(-355.235514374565,-375.,100.));
#486=CARTESIAN_POINT('',(-319.200833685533,-282.590755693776,58.2859511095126));
#487=CARTESIAN_POINT('',(-293.075279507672,-226.888141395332,104.97090627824));
#488=CARTESIAN_POINT('',(-324.119079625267,-68.6572837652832,122.102733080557));
#489=CARTESIAN_POINT('',(-398.972481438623,73.039345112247,53.3701087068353));
#490=CARTESIAN_POINT('',(-423.398679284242,233.384819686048,47.4380317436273));
#491=CARTESIAN_POINT('',(-392.720188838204,253.575952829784,124.952096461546));
#492=CARTESIAN_POINT('',(-355.235514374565,375.,100.));
#493=CARTESIAN_POINT('',(-536.684515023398,-375.,100.));
#494=CARTESIAN_POINT('',(-494.827225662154,-277.129657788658,52.0422385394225));
#495=CARTESIAN_POINT('',(-464.573647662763,-205.017596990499,67.039018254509));
#496=CARTESIAN_POINT('',(-506.334367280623,-72.2467511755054,96.5036749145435));
#497=CARTESIAN_POINT('',(-600.216684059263,9.35641022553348,95.9941925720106));
#498=CARTESIAN_POINT('',(-628.122542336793,166.946160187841,106.349064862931));
#499=CARTESIAN_POINT('',(-587.011939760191,237.095914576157,138.331902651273));
#500=CARTESIAN_POINT('',(-536.684515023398,375.,100.));
#501=CARTESIAN_POINT('',(-644.685568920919,-375.,100.));
#502=CARTESIAN_POINT('',(-644.685568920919,-302.078506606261,100.));
#503=CARTESIAN_POINT('',(-644.685568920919,-237.237234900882,127.59081546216));
#504=CARTESIAN_POINT('',(-644.685568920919,-62.4430976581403,126.406497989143));
#505=CARTESIAN_POINT('',(-644.685568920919,76.6951111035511,77.5962366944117));
#506=CARTESIAN_POINT('',(-644.685568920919,248.895340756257,64.9137717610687));
#507=CARTESIAN_POINT('',(-644.685568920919,298.882075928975,100.));
#508=CARTESIAN_POINT('',(-644.685568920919,375.,100.));
#509=CARTESIAN_POINT('',(-750.,-375.,100.));
#510=CARTESIAN_POINT('',(-750.,-302.078506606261,100.));
#511=CARTESIAN_POINT('',(-750.,-224.483786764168,100.));
#512=CARTESIAN_POINT('',(-750.,-61.5160152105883,100.));
#513=CARTESIAN_POINT('',(-750.,39.4445673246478,100.));
#514=CARTESIAN_POINT('',(-750.,211.849847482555,100.));
#515=CARTESIAN_POINT('',(-750.,298.882075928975,100.));
#516=CARTESIAN_POINT('',(-750.,375.,100.));
#517=B_SPLINE_SURFACE_WITH_KNOTS('',3,3,((#437,#438,#439,#440,#441,#442,#443,#444),(#445,#446,
#447,#448,#449,#450,#451,#452),(#453,#454,#455,#456,#457,#458,#459,#460),(#461,#462,#463,#464,
#465,#466,#467,#468),(#469,#470,#471,#472,#473,#474,#475,#476),(#477,#478,#479,#480,#481,#482,
#483,#484),(#485,#486,#487,#488,#489,#490,#491,#492),(#493,#494,#495,#496,#497,#498,#499,#500),
(#501,#502,#503,#504,#505,#506,#507,#508),(#509,#510,#511,#512,#513,#514,#515,#516)),
.UNSPECIFIED.,.F.,.F.,.F.,(4,1,1,1,1,1,1,4),(4,1,1,1,1,4),(0.,0.161829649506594,
0.33728011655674,0.430707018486,0.637101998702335,0.783997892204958,0.789371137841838,1.),(0.,
0.291685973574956,0.310378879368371,0.65187108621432,0.695528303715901,1.),.UNSPECIFIED.);
#518=CARTESIAN_POINT('',(-300.,-375.,100.));
#519=CARTESIAN_POINT('',(-300.,-374.047224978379,99.7492324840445));
#520=CARTESIAN_POINT('',(-300.,-373.092406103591,99.5062937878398));
#521=CARTESIAN_POINT('',(-300.,-371.178852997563,99.0363287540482));
#522=CARTESIAN_POINT('',(-300.,-370.220118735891,98.8093025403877));
#523=CARTESIAN_POINT('',(-300.,-367.340097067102,98.1528845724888));
#524=CARTESIAN_POINT('',(-300.,-365.41323117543,97.7476896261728));
#525=CARTESIAN_POINT('',(-300.,-361.548063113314,97.0037958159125));
#526=CARTESIAN_POINT('',(-300.,-359.609769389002,96.6650529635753));
#527=CARTESIAN_POINT('',(-300.,-355.723393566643,96.0548477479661));
#528=CARTESIAN_POINT('',(-300.,-353.775315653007,95.7833587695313));
#529=CARTESIAN_POINT('',(-300.,-349.871187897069,95.3078382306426));
#530=CARTESIAN_POINT('',(-300.,-347.915139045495,95.1037985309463));
#531=CARTESIAN_POINT('',(-300.,-344.032931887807,94.7658154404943));
#532=CARTESIAN_POINT('',(-300.,-342.106878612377,94.6306621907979));
#533=CARTESIAN_POINT('',(-300.,-338.251191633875,94.4238091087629));
#534=CARTESIAN_POINT('',(-300.,-336.321557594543,94.3521155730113));
#535=CARTESIAN_POINT('',(-300.,-332.460750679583,94.2704312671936));
#536=CARTESIAN_POINT('',(-300.,-330.529577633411,94.2604487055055));
#537=CARTESIAN_POINT('',(-300.,-326.667730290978,94.2998404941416));
#538=CARTESIAN_POINT('',(-300.,-324.737056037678,94.3492188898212));
#539=CARTESIAN_POINT('',(-300.,-320.878256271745,94.5044514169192));
#540=CARTESIAN_POINT('',(-300.,-318.950130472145,94.6102985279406));
#541=CARTESIAN_POINT('',(-300.,-314.813204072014,94.8947530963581));
#542=CARTESIAN_POINT('',(-300.,-312.604984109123,95.081794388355));
#543=CARTESIAN_POINT('',(-300.,-308.194624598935,95.5206178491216));
#544=CARTESIAN_POINT('',(-300.,-305.992486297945,95.772412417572));
#545=CARTESIAN_POINT('',(-300.,-301.595702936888,96.3351071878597));
#546=CARTESIAN_POINT('',(-300.,-299.401058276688,96.646010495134));
#547=CARTESIAN_POINT('',(-300.,-295.019061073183,97.3213885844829));
#548=CARTESIAN_POINT('',(-300.,-292.831712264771,97.6858874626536));
#549=CARTESIAN_POINT('',(-300.,-288.465726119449,98.4627498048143));
#550=CARTESIAN_POINT('',(-300.,-286.287088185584,98.8751099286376));
#551=CARTESIAN_POINT('',(-300.,-281.938365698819,99.742356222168));
#552=CARTESIAN_POINT('',(-300.,-279.768281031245,100.197241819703));
#553=CARTESIAN_POINT('',(-300.,-274.3313332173,101.38605759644));
#554=CARTESIAN_POINT('',(-300.,-271.069711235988,102.143958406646));
#555=CARTESIAN_POINT('',(-300.,-264.563402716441,103.728801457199));
#556=CARTESIAN_POINT('',(-300.,-261.318716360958,104.555744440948));
#557=CARTESIAN_POINT('',(-300.,-254.844548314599,106.263342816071));
#558=CARTESIAN_POINT('',(-300.,-251.615062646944,107.143983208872));
#559=CARTESIAN_POINT('',(-300.,-245.167170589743,108.944645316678));
#560=CARTESIAN_POINT('',(-300.,-241.948764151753,109.86466685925));
#561=CARTESIAN_POINT('',(-300.,-235.840787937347,111.636012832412));
#562=CARTESIAN_POINT('',(-300.,-232.950536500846,112.485000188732));
#563=CARTESIAN_POINT('',(-300.,-227.172501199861,114.191352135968));
#564=CARTESIAN_POINT('',(-300.,-224.284717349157,115.048716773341));
#565=CARTESIAN_POINT('',(-300.,-218.507601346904,116.759149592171));
#566=CARTESIAN_POINT('',(-300.,-215.61826908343,117.612217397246));
#567=CARTESIAN_POINT('',(-300.,-209.839780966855,119.297972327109));
#568=CARTESIAN_POINT('',(-300.,-206.950635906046,120.130696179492));
#569=CARTESIAN_POINT('',(-300.,-201.162707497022,121.76130833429));
#570=CARTESIAN_POINT('',(-300.,-198.263924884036,122.559199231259));
#571=CARTESIAN_POINT('',(-300.,-192.452510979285,124.102131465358));
#572=CARTESIAN_POINT('',(-300.,-189.539881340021,124.847178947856));
#573=CARTESIAN_POINT('',(-300.,-185.51968178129,125.822610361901));
#574=CARTESIAN_POINT('',(-300.,-184.419637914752,126.084091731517));
#575=CARTESIAN_POINT('',(-300.,-182.21688394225,126.595722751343));
#576=CARTESIAN_POINT('',(-300.,-181.114173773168,126.845872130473));
#577=CARTESIAN_POINT('',(-300.,-178.905989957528,127.333740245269));
#578=CARTESIAN_POINT('',(-300.,-177.800516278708,127.571458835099));
#579=CARTESIAN_POINT('',(-300.,-175.586704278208,128.033367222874));
#580=CARTESIAN_POINT('',(-300.,-174.478365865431,128.257556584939));
#581=CARTESIAN_POINT('',(-300.,-172.259872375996,128.691102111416));
#582=CARTESIAN_POINT('',(-300.,-171.14971999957,128.900472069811));
#583=CARTESIAN_POINT('',(-300.,-168.926554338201,129.303521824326));
#584=CARTESIAN_POINT('',(-300.,-167.813541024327,129.497201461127));
#585=CARTESIAN_POINT('',(-300.,-165.584729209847,129.867876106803));
#586=CARTESIAN_POINT('',(-300.,-164.468930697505,130.044871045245));
#587=CARTESIAN_POINT('',(-300.,-162.234531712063,130.380656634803));
#588=CARTESIAN_POINT('',(-300.,-161.115931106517,130.539446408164));
#589=CARTESIAN_POINT('',(-300.,-159.04869096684,130.814322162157));
#590=CARTESIAN_POINT('',(-300.,-158.100424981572,130.933217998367));
#591=CARTESIAN_POINT('',(-300.,-156.202127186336,131.156053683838));
#592=CARTESIAN_POINT('',(-300.,-155.252095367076,131.259993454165));
#593=CARTESIAN_POINT('',(-300.,-153.350129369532,131.452191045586));
#594=CARTESIAN_POINT('',(-300.,-152.398194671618,131.54044373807));
#595=CARTESIAN_POINT('',(-300.,-150.492951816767,131.700597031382));
#596=CARTESIAN_POINT('',(-300.,-149.539643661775,131.772497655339));
#597=CARTESIAN_POINT('',(-300.,-147.631668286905,131.900430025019));
#598=CARTESIAN_POINT('',(-300.,-146.677000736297,131.956456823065));
#599=CARTESIAN_POINT('',(-300.,-144.766883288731,132.053040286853));
#600=CARTESIAN_POINT('',(-300.,-143.81143338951,132.093596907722));
#601=CARTESIAN_POINT('',(-300.,-141.899724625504,132.159683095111));
#602=CARTESIAN_POINT('',(-300.,-140.943465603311,132.185208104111));
#603=CARTESIAN_POINT('',(-300.,-139.030679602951,132.221639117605));
#604=CARTESIAN_POINT('',(-300.,-138.074152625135,132.232545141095));
#605=CARTESIAN_POINT('',(-300.,-135.20425269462,132.243971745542));
#606=CARTESIAN_POINT('',(-300.,-133.290758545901,132.223194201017));
#607=CARTESIAN_POINT('',(-300.,-129.465545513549,132.128185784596));
#608=CARTESIAN_POINT('',(-300.,-127.553826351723,132.053965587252));
#609=CARTESIAN_POINT('',(-300.,-123.724072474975,131.854848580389));
#610=CARTESIAN_POINT('',(-300.,-121.806050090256,131.729716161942));
#611=CARTESIAN_POINT('',(-300.,-117.974145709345,131.431961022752));
#612=CARTESIAN_POINT('',(-300.,-116.060262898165,131.259348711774));
#613=CARTESIAN_POINT('',(-300.,-112.237177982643,130.869661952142));
#614=CARTESIAN_POINT('',(-300.,-110.327975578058,130.652590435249));
#615=CARTESIAN_POINT('',(-300.,-106.514815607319,130.176867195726));
#616=CARTESIAN_POINT('',(-300.,-104.610857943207,129.918216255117));
#617=CARTESIAN_POINT('',(-300.,-100.808761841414,129.362084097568));
#618=CARTESIAN_POINT('',(-300.,-98.9106230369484,129.064605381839));
#619=CARTESIAN_POINT('',(-300.,-95.1207737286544,128.433445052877));
#620=CARTESIAN_POINT('',(-300.,-93.2290620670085,128.099770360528));
#621=CARTESIAN_POINT('',(-300.,-88.2657578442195,127.178414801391));
#622=CARTESIAN_POINT('',(-300.,-85.1993221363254,126.562822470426));
#623=CARTESIAN_POINT('',(-300.,-79.0834978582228,125.251618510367));
#624=CARTESIAN_POINT('',(-300.,-76.0341105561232,124.556001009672));
#625=CARTESIAN_POINT('',(-300.,-69.9516742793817,123.093161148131));
#626=CARTESIAN_POINT('',(-300.,-66.9186303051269,122.325918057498));
#627=CARTESIAN_POINT('',(-300.,-60.8695011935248,120.727706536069));
#628=CARTESIAN_POINT('',(-300.,-57.8534157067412,119.896739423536));
#629=CARTESIAN_POINT('',(-300.,-51.8334606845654,118.176753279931));
#630=CARTESIAN_POINT('',(-300.,-48.8296132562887,117.287657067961));
#631=CARTESIAN_POINT('',(-300.,-42.8374756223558,115.458559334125));
#632=CARTESIAN_POINT('',(-300.,-39.8491854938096,114.518557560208));
#633=CARTESIAN_POINT('',(-300.,-33.8832070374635,112.591821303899));
#634=CARTESIAN_POINT('',(-300.,-30.9055388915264,111.605024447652));
#635=CARTESIAN_POINT('',(-300.,-24.9639904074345,109.590843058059));
#636=CARTESIAN_POINT('',(-300.,-22.0001100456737,108.563458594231));
#637=CARTESIAN_POINT('',(-300.,-16.0828163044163,106.47173789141));
#638=CARTESIAN_POINT('',(-300.,-13.1294129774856,105.407373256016));
#639=CARTESIAN_POINT('',(-300.,-7.23440071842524,103.246508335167));
#640=CARTESIAN_POINT('',(-300.,-4.29279178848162,102.150008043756));
#641=CARTESIAN_POINT('',(-300.,1.57910672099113,99.9287774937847));
#642=CARTESIAN_POINT('',(-300.,4.50939831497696,98.8040525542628));
#643=CARTESIAN_POINT('',(-300.,10.3602405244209,96.5295741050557));
#644=CARTESIAN_POINT('',(-300.,13.2807911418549,95.3798206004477));
#645=CARTESIAN_POINT('',(-300.,19.1452770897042,93.0456626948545));
#646=CARTESIAN_POINT('',(-300.,22.089115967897,91.8610161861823));
#647=CARTESIAN_POINT('',(-300.,27.9689516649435,89.4724058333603));
#648=CARTESIAN_POINT('',(-300.,30.9049484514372,88.2684419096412));
#649=CARTESIAN_POINT('',(-300.,39.6958735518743,84.6347825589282));
#650=CARTESIAN_POINT('',(-300.,45.5406569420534,82.1805492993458));
#651=CARTESIAN_POINT('',(-300.,57.2063105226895,77.2305539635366));
#652=CARTESIAN_POINT('',(-300.,63.027197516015,74.7348313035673));
#653=CARTESIAN_POINT('',(-300.,71.7490658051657,70.9750827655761));
#654=CARTESIAN_POINT('',(-300.,74.6537364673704,69.7195930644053));
#655=CARTESIAN_POINT('',(-300.,80.4617736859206,67.2055997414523));
#656=CARTESIAN_POINT('',(-300.,83.3651402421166,65.9470961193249));
#657=CARTESIAN_POINT('',(-300.,89.1700832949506,63.430551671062));
#658=CARTESIAN_POINT('',(-300.,92.0716598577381,62.1725109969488));
#659=CARTESIAN_POINT('',(-300.,97.8759506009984,59.6590580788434));
#660=CARTESIAN_POINT('',(-300.,100.778664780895,58.4036458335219));
#661=CARTESIAN_POINT('',(-300.,106.585296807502,55.8990958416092));
#662=CARTESIAN_POINT('',(-300.,109.489213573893,54.6499555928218));
#663=CARTESIAN_POINT('',(-300.,115.300945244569,52.1607809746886));
#664=CARTESIAN_POINT('',(-300.,118.208760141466,50.9207465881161));
#665=CARTESIAN_POINT('',(-300.,123.88504684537,48.5149271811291));
#666=CARTESIAN_POINT('',(-300.,126.653253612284,47.3485175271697));
#667=CARTESIAN_POINT('',(-300.,132.19665183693,45.0307470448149));
#668=CARTESIAN_POINT('',(-300.,134.97184464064,43.8793894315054));
#669=CARTESIAN_POINT('',(-300.,140.53184010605,41.5955418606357));
#670=CARTESIAN_POINT('',(-300.,143.31664733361,40.4630630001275));
#671=CARTESIAN_POINT('',(-300.,148.898790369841,38.2215358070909));
#672=CARTESIAN_POINT('',(-300.,151.696135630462,37.1125109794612));
#673=CARTESIAN_POINT('',(-300.,157.306687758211,34.9234191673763));
#674=CARTESIAN_POINT('',(-300.,160.11991134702,33.8433948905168));
#675=CARTESIAN_POINT('',(-300.,164.353175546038,32.2508159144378));
#676=CARTESIAN_POINT('',(-300.,165.767870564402,31.7240384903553));
#677=CARTESIAN_POINT('',(-300.,168.601175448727,30.6811265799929));
#678=CARTESIAN_POINT('',(-300.,170.019785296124,30.1649920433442));
#679=CARTESIAN_POINT('',(-300.,172.843700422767,29.1508986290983));
#680=CARTESIAN_POINT('',(-300.,174.248953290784,28.6527939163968));
#681=CARTESIAN_POINT('',(-300.,177.063977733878,27.6695048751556));
#682=CARTESIAN_POINT('',(-300.,178.473749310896,27.184320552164));
#683=CARTESIAN_POINT('',(-300.,181.298612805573,26.2282634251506));
#684=CARTESIAN_POINT('',(-300.,182.713706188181,25.757394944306));
#685=CARTESIAN_POINT('',(-300.,185.549196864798,24.8318868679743));
#686=CARTESIAN_POINT('',(-300.,186.96959415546,24.3772472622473));
#687=CARTESIAN_POINT('',(-300.,189.81447109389,23.4867584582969));
#688=CARTESIAN_POINT('',(-300.,191.238944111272,23.0508881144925));
#689=CARTESIAN_POINT('',(-300.,194.094054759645,22.1997604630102));
#690=CARTESIAN_POINT('',(-300.,195.524692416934,21.7845032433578));
#691=CARTESIAN_POINT('',(-300.,198.389437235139,20.9782988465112));
#692=CARTESIAN_POINT('',(-300.,199.823529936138,20.5873004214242));
#693=CARTESIAN_POINT('',(-300.,202.698722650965,19.8319524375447));
#694=CARTESIAN_POINT('',(-300.,204.139822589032,19.4676025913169));
#695=CARTESIAN_POINT('',(-300.,207.026019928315,18.7705603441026));
#696=CARTESIAN_POINT('',(-300.,208.471099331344,18.4377937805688));
#697=CARTESIAN_POINT('',(-300.,211.369131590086,17.8079777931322));
#698=CARTESIAN_POINT('',(-300.,212.822084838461,17.5109301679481));
#699=CARTESIAN_POINT('',(-300.,215.735071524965,16.9589787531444));
#700=CARTESIAN_POINT('',(-300.,217.195099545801,16.7040467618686));
#701=CARTESIAN_POINT('',(-300.,219.390893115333,16.3590032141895));
#702=CARTESIAN_POINT('',(-300.,220.123746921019,16.2502188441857));
#703=CARTESIAN_POINT('',(-300.,221.591340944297,16.0462818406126));
#704=CARTESIAN_POINT('',(-300.,222.326081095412,15.9511287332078));
#705=CARTESIAN_POINT('',(-300.,223.487423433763,15.8127057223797));
#706=CARTESIAN_POINT('',(-300.,223.913437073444,15.7644660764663));
#707=CARTESIAN_POINT('',(-300.,224.766023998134,15.6732777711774));
#708=CARTESIAN_POINT('',(-300.,225.192597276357,15.6303290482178));
#709=CARTESIAN_POINT('',(-300.,226.473259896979,15.5098494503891));
#710=CARTESIAN_POINT('',(-300.,227.328160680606,15.4407009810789));
#711=CARTESIAN_POINT('',(-300.,229.039653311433,15.3274628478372));
#712=CARTESIAN_POINT('',(-300.,229.896245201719,15.2833738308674));
#713=CARTESIAN_POINT('',(-300.,231.610637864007,15.2233770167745));
#714=CARTESIAN_POINT('',(-300.,232.468438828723,15.2074743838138));
#715=CARTESIAN_POINT('',(-300.,233.753313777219,15.2075647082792));
#716=CARTESIAN_POINT('',(-300.,234.180406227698,15.2115522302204));
#717=CARTESIAN_POINT('',(-300.,235.034432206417,15.2278024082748));
#718=CARTESIAN_POINT('',(-300.,235.461365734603,15.2400650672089));
#719=CARTESIAN_POINT('',(-300.,236.741792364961,15.2896981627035));
#720=CARTESIAN_POINT('',(-300.,237.594833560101,15.3399138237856));
#721=CARTESIAN_POINT('',(-300.,239.297811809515,15.4769659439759));
#722=CARTESIAN_POINT('',(-300.,240.147749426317,15.563795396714));
#723=CARTESIAN_POINT('',(-300.,241.842680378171,15.7763354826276));
#724=CARTESIAN_POINT('',(-300.,242.687674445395,15.9020402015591));
#725=CARTESIAN_POINT('',(-300.,244.189615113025,16.1629399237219));
#726=CARTESIAN_POINT('',(-300.,244.847932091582,16.2902838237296));
#727=CARTESIAN_POINT('',(-300.,246.159040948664,16.5710342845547));
#728=CARTESIAN_POINT('',(-300.,246.811832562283,16.7244420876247));
#729=CARTESIAN_POINT('',(-300.,248.110465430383,17.0579520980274));
#730=CARTESIAN_POINT('',(-300.,248.756307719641,17.2380502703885));
#731=CARTESIAN_POINT('',(-300.,250.039797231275,17.6253954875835));
#732=CARTESIAN_POINT('',(-300.,250.6774446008,17.8326420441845));
#733=CARTESIAN_POINT('',(-300.,251.943650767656,18.274626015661));
#734=CARTESIAN_POINT('',(-300.,252.572202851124,18.5093826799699));
#735=CARTESIAN_POINT('',(-300.,253.818449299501,19.0061733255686));
#736=CARTESIAN_POINT('',(-300.,254.436143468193,19.2682077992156));
#737=CARTESIAN_POINT('',(-300.,255.659449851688,19.8191662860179));
#738=CARTESIAN_POINT('',(-300.,256.265061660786,20.1080912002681));
#739=CARTESIAN_POINT('',(-300.,257.463029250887,20.7121017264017));
#740=CARTESIAN_POINT('',(-300.,258.055385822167,21.0271857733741));
#741=CARTESIAN_POINT('',(-300.,259.418869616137,21.7905966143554));
#742=CARTESIAN_POINT('',(-300.,260.184589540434,22.2486181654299));
#743=CARTESIAN_POINT('',(-300.,261.689457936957,23.2063845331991));
#744=CARTESIAN_POINT('',(-300.,262.428604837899,23.7061318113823));
#745=CARTESIAN_POINT('',(-300.,263.8794833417,24.743883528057));
#746=CARTESIAN_POINT('',(-300.,264.591215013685,25.2818878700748));
#747=CARTESIAN_POINT('',(-300.,265.986876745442,26.3921324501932));
#748=CARTESIAN_POINT('',(-300.,266.670818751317,26.9643577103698));
#749=CARTESIAN_POINT('',(-300.,268.011817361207,28.1393475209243));
#750=CARTESIAN_POINT('',(-300.,268.668875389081,28.7421104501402));
#751=CARTESIAN_POINT('',(-300.,269.95722578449,29.9742657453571));
#752=CARTESIAN_POINT('',(-300.,270.588522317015,30.6036537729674));
#753=CARTESIAN_POINT('',(-300.,272.252002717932,32.3252484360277));
#754=CARTESIAN_POINT('',(-300.,273.262140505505,33.4387877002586));
#755=CARTESIAN_POINT('',(-300.,275.224691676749,35.7164535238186));
#756=CARTESIAN_POINT('',(-300.,276.177063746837,36.8806152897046));
#757=CARTESIAN_POINT('',(-300.,278.035765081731,39.2469757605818));
#758=CARTESIAN_POINT('',(-300.,278.942042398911,40.4492150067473));
#759=CARTESIAN_POINT('',(-300.,280.719242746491,42.8797063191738));
#760=CARTESIAN_POINT('',(-300.,281.590158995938,44.1079633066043));
#761=CARTESIAN_POINT('',(-300.,283.316062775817,46.5927491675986));
#762=CARTESIAN_POINT('',(-300.,284.170822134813,47.8494355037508));
#763=CARTESIAN_POINT('',(-300.,285.866479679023,50.3704892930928));
#764=CARTESIAN_POINT('',(-300.,286.707389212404,51.6348491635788));
#765=CARTESIAN_POINT('',(-300.,288.386674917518,54.1646604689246));
#766=CARTESIAN_POINT('',(-300.,289.225051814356,55.4301114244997));
#767=CARTESIAN_POINT('',(-300.,290.910021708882,57.9558771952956));
#768=CARTESIAN_POINT('',(-300.,291.756616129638,59.2161910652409));
#769=CARTESIAN_POINT('',(-300.,293.758459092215,62.1507997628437));
#770=CARTESIAN_POINT('',(-300.,294.920848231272,63.8202628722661));
#771=CARTESIAN_POINT('',(-300.,297.300490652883,67.1203939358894));
#772=CARTESIAN_POINT('',(-300.,298.517749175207,68.7510581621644));
#773=CARTESIAN_POINT('',(-300.,300.400038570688,71.1535642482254));
#774=CARTESIAN_POINT('',(-300.,301.037050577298,71.9473623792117));
#775=CARTESIAN_POINT('',(-300.,302.332022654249,73.51765279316));
#776=CARTESIAN_POINT('',(-300.,302.989981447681,74.2941461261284));
#777=CARTESIAN_POINT('',(-300.,304.32157552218,75.8186979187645));
#778=CARTESIAN_POINT('',(-300.,304.99496057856,76.5669745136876));
#779=CARTESIAN_POINT('',(-300.,306.365889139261,78.0410942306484));
#780=CARTESIAN_POINT('',(-300.,307.063432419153,78.7669375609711));
#781=CARTESIAN_POINT('',(-300.,308.483810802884,80.1931106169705));
#782=CARTESIAN_POINT('',(-300.,309.206639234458,80.8934469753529));
#783=CARTESIAN_POINT('',(-300.,310.678685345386,82.2659029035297));
#784=CARTESIAN_POINT('',(-300.,311.427903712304,82.9380217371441));
#785=CARTESIAN_POINT('',(-300.,312.952472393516,84.250564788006));
#786=CARTESIAN_POINT('',(-300.,313.727798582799,84.8910169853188));
#787=CARTESIAN_POINT('',(-300.,315.305089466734,86.1380936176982));
#788=CARTESIAN_POINT('',(-300.,316.107051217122,86.7447217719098));
#789=CARTESIAN_POINT('',(-300.,317.736193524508,87.9210760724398));
#790=CARTESIAN_POINT('',(-300.,318.563343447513,88.4908446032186));
#791=CARTESIAN_POINT('',(-300.,320.242822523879,89.592209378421));
#792=CARTESIAN_POINT('',(-300.,321.095154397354,90.1238014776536));
#793=CARTESIAN_POINT('',(-300.,322.823431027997,91.1470594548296));
#794=CARTESIAN_POINT('',(-300.,323.699375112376,91.6387264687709));
#795=CARTESIAN_POINT('',(-300.,325.472987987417,92.5809227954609));
#796=CARTESIAN_POINT('',(-300.,326.3706543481,93.0314566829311));
#797=CARTESIAN_POINT('',(-300.,328.188965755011,93.8923294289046));
#798=CARTESIAN_POINT('',(-300.,329.109681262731,94.3025193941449));
#799=CARTESIAN_POINT('',(-300.,330.968783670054,95.0807651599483));
#800=CARTESIAN_POINT('',(-300.,331.907171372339,95.4488190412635));
#801=CARTESIAN_POINT('',(-300.,333.799349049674,96.1431713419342));
#802=CARTESIAN_POINT('',(-300.,334.753140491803,96.4694657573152));
#803=CARTESIAN_POINT('',(-300.,336.673732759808,97.0810543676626));
#804=CARTESIAN_POINT('',(-300.,337.640533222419,97.3663497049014));
#805=CARTESIAN_POINT('',(-300.,339.43237167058,97.8554581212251));
#806=CARTESIAN_POINT('',(-300.,340.255844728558,98.06503212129));
#807=CARTESIAN_POINT('',(-300.,341.909307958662,98.4567437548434));
#808=CARTESIAN_POINT('',(-300.,342.739298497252,98.6388798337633));
#809=CARTESIAN_POINT('',(-300.,345.237743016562,99.1456229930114));
#810=CARTESIAN_POINT('',(-300.,346.914387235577,99.4304886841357));
#811=CARTESIAN_POINT('',(-300.,350.281335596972,99.9026504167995));
#812=CARTESIAN_POINT('',(-300.,351.971642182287,100.089928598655));
#813=CARTESIAN_POINT('',(-300.,355.361460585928,100.375942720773));
#814=CARTESIAN_POINT('',(-300.,357.060980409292,100.474582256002));
#815=CARTESIAN_POINT('',(-300.,360.462180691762,100.591657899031));
#816=CARTESIAN_POINT('',(-300.,362.163860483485,100.610114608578));
#817=CARTESIAN_POINT('',(-300.,365.565981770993,100.57504043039));
#818=CARTESIAN_POINT('',(-300.,367.266423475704,100.521528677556));
#819=CARTESIAN_POINT('',(-300.,369.469484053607,100.410279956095));
#820=CARTESIAN_POINT('',(-300.,369.97373583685,100.381963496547));
#821=CARTESIAN_POINT('',(-300.,370.981845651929,100.319819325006));
#822=CARTESIAN_POINT('',(-300.,371.48570372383,100.285992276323));
#823=CARTESIAN_POINT('',(-300.,372.491523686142,100.213110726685));
#824=CARTESIAN_POINT('',(-300.,372.993486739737,100.174072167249));
#825=CARTESIAN_POINT('',(-300.,373.997044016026,100.090851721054));
#826=CARTESIAN_POINT('',(-300.,374.498638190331,100.04666925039));
#827=CARTESIAN_POINT('',(-300.,375.,100.));
#828=B_SPLINE_CURVE_WITH_KNOTS('',3,(#518,#519,#520,#521,#522,#523,#524,#525,#526,#527,#528,
#529,#530,#531,#532,#533,#534,#535,#536,#537,#538,#539,#540,#541,#542,#543,#544,#545,#546,#547,
#548,#549,#550,#551,#552,#553,#554,#555,#556,#557,#558,#559,#560,#561,#562,#563,#564,#565,#566,
#567,#568,#569,#570,#571,#572,#573,#574,#575,#576,#577,#578,#579,#580,#581,#582,#583,#584,#585,
#586,#587,#588,#589,#590,#591,#592,#593,#594,#595,#596,#597,#598,#599,#600,#601,#602,#603,#604,
#605,#606,#607,#608,#609,#610,#611,#612,#613,#614,#615,#616,#617,#618,#619,#620,#621,#622,#623,
#624,#625,#626,#627,#628,#629,#630,#631,#632,#633,#634,#635,#636,#637,#638,#639,#640,#641,#642,
#643,#644,#645,#646,#647,#648,#649,#650,#651,#652,#653,#654,#655,#656,#657,#658,#659,#660,#661,
#662,#663,#664,#665,#666,#667,#668,#669,#670,#671,#672,#673,#674,#675,#676,#677,#678,#679,#680,
#681,#682,#683,#684,#685,#686,#687,#688,#689,#690,#691,#692,#693,#694,#695,#696,#697,#698,#699,
#700,#701,#702,#703,#704,#705,#706,#707,#708,#709,#710,#711,#712,#713,#714,#715,#716,#717,#718,
#719,#720,#721,#722,#723,#724,#725,#726,#727,#728,#729,#730,#731,#732,#733,#734,#735,#736,#737,
#738,#739,#740,#741,#742,#743,#744,#745,#746,#747,#748,#749,#750,#751,#752,#753,#754,#755,#756,
#757,#758,#759,#760,#761,#762,#763,#764,#765,#766,#767,#768,#769,#770,#771,#772,#773,#774,#775,
#776,#777,#778,#779,#780,#781,#782,#783,#784,#785,#786,#787,#788,#789,#790,#791,#792,#793,#794,
#795,#796,#797,#798,#799,#800,#801,#802,#803,#804,#805,#806,#807,#808,#809,#810,#811,#812,#813,
#814,#815,#816,#817,#818,#819,#820,#821,#822,#823,#824,#825,#826,#827),.UNSPECIFIED.,.F.,.F.,(4,
2,2,2,2,2,2,2,2,2,2,2,2,2,2,2,2,2,2,2,2,2,2,2,2,2,2,2,2,2,2,2,2,2,2,2,2,2,2,2,2,2,2,2,2,2,2,2,2,
2,2,2,2,2,2,2,2,2,2,2,2,2,2,2,2,2,2,2,2,2,2,2,2,2,2,2,2,2,2,2,2,2,2,2,2,2,2,2,2,2,2,2,2,2,2,2,2,
2,2,2,2,2,2,2,2,2,2,2,2,2,2,2,2,2,2,2,2,2,2,2,2,2,2,2,2,2,2,2,2,2,2,2,2,2,2,2,2,2,2,2,2,2,2,2,2,
2,2,2,2,2,2,2,2,2,4),(0.,2.95560191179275,5.91122683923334,11.8170203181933,17.7188911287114,
23.6184225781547,29.5172418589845,35.3085433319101,41.1004193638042,46.8930657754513,
52.6861069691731,58.4784281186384,65.1257471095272,71.7743399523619,78.4232821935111,
85.0752229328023,91.7266997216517,98.3780870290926,108.422629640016,118.467280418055,
128.509138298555,138.550952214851,147.588012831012,156.625123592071,165.663012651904,
174.683156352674,183.702627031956,192.721047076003,196.11308092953,199.505195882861,
202.897350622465,206.289614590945,209.678678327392,213.067776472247,216.456888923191,
219.846164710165,222.713126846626,225.580104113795,228.448016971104,231.315925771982,
234.184727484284,237.053537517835,239.923216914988,242.792892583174,248.532837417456,
254.271636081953,260.037300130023,265.801701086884,271.565722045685,277.32963460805,
283.093176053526,288.855617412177,298.237166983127,307.619405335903,317.004367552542,
326.389135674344,335.786627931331,345.184166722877,354.594604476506,364.005026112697,
373.422840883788,382.84065740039,392.256712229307,401.672765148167,411.192463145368,
420.712200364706,439.729313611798,458.729289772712,468.222459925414,477.715631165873,
487.20332423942,496.691012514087,506.174554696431,515.65807893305,524.669776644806,
533.683368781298,542.702084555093,551.729446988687,560.769445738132,565.298175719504,
569.826884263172,574.299589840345,578.772297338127,583.246342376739,587.720384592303,
592.189246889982,596.658128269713,601.1172226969,605.576269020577,610.02457138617,
614.473097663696,618.918632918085,621.141183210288,623.363656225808,624.649834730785,
625.935997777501,628.508720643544,631.081509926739,633.65477053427,634.936031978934,
636.217293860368,638.780051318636,641.342318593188,643.90419625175,645.915270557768,
647.926440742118,649.937307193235,651.948137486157,653.960383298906,655.972665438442,
657.985015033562,659.997244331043,662.672502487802,665.347918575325,668.023327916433,
670.697574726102,673.371679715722,676.045350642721,680.552982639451,685.063801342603,
689.57959582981,694.096252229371,698.655572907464,703.210950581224,707.764869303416,
712.319591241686,718.421817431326,724.524627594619,727.577703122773,730.630592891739,
733.650086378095,736.669551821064,739.688226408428,742.706979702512,745.723016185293,
748.738720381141,751.750892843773,754.763391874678,757.775805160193,760.787883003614,
763.810690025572,766.833634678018,769.856868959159,772.880018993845,775.428703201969,
777.977531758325,783.076065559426,788.175532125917,793.280538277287,798.384232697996,
803.486570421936,805.001695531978,806.516638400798,808.027049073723,809.537631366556),.UNSPECIFIED.);
#829=CARTESIAN_POINT('',(-300.,-375.,100.));
#830=VERTEX_POINT('',#829);
#831=CARTESIAN_POINT('',(-300.,375.,100.));
#832=VERTEX_POINT('',#831);
#833=EDGE_CURVE('E11',#830,#832,#828,.T.);
#834=CARTESIAN_POINT('',(-750.,-375.,100.));
#835=CARTESIAN_POINT('',(-644.685568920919,-375.,100.));
#836=CARTESIAN_POINT('',(-536.684515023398,-375.,100.));
#837=CARTESIAN_POINT('',(-355.235514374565,-375.,100.));
#838=CARTESIAN_POINT('',(-175.903454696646,-375.,100.));
#839=CARTESIAN_POINT('',(47.4554331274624,-375.,100.));
#840=CARTESIAN_POINT('',(285.091607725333,-375.,100.));
#841=CARTESIAN_POINT('',(500.445116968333,-375.,100.));
#842=CARTESIAN_POINT('',(669.085175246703,-375.,100.));
#843=CARTESIAN_POINT('',(750.,-375.,100.));
#844=B_SPLINE_CURVE_WITH_KNOTS('',3,(#834,#835,#836,#837,#838,#839,#840,#841,#842,#843),
.UNSPECIFIED.,.F.,.F.,(4,1,1,1,1,1,1,4),(0.,0.210628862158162,0.216002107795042,
0.362898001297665,0.569292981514,0.66271988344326,0.838170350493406,1.),.UNSPECIFIED.);
#845=EDGE_CURVE('E97',#830,#378,#844,.T.);
#846=CARTESIAN_POINT('',(750.,375.,100.));
#847=CARTESIAN_POINT('',(669.085175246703,375.,100.));
#848=CARTESIAN_POINT('',(500.445116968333,375.,100.));
#849=CARTESIAN_POINT('',(285.091607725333,375.,100.));
#850=CARTESIAN_POINT('',(47.4554331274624,375.,100.));
#851=CARTESIAN_POINT('',(-175.903454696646,375.,100.));
#852=CARTESIAN_POINT('',(-355.235514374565,375.,100.));
#853=CARTESIAN_POINT('',(-536.684515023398,375.,100.));
#854=CARTESIAN_POINT('',(-644.685568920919,375.,100.));
#855=CARTESIAN_POINT('',(-750.,375.,100.));
#856=B_SPLINE_CURVE_WITH_KNOTS('',3,(#846,#847,#848,#849,#850,#851,#852,#853,#854,#855),
.UNSPECIFIED.,.F.,.F.,(4,1,1,1,1,1,1,4),(0.,0.161829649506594,0.33728011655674,0.430707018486,
0.637101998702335,0.783997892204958,0.789371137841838,1.),.UNSPECIFIED.);
#857=EDGE_CURVE('E94',#376,#832,#856,.T.);
#858=ORIENTED_EDGE('',*,*,#833,.F.);
#859=ORIENTED_EDGE('',*,*,#845,.T.);
#860=ORIENTED_EDGE('',*,*,#379,.F.);
#861=ORIENTED_EDGE('',*,*,#857,.T.);
#862=EDGE_LOOP('',(#858,#859,#860,#861));
#863=FACE_BOUND('',#862,.T.);
#864=ADVANCED_FACE('F110',(#863),#517,.F.);
#865=CARTESIAN_POINT('',(-750.,375.,253.111113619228));
#866=DIRECTION('',(0.,-1.,0.));
#867=DIRECTION('',(0.,0.,-1.));
#868=AXIS2_PLACEMENT_3D('',#865,#866,#867);
#869=PLANE('',#868);
#870=DIRECTION('',(0.,0.,-1.));
#871=VECTOR('',#870,1.);
#872=CARTESIAN_POINT('',(-300.,375.,253.120113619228));
#873=LINE('',#872,#871);
#874=EDGE_CURVE('E154',#832,#424,#873,.T.);
#875=ORIENTED_EDGE('',*,*,#874,.F.);
#876=ORIENTED_EDGE('',*,*,#857,.F.);
#877=ORIENTED_EDGE('',*,*,#401,.T.);
#878=ORIENTED_EDGE('',*,*,#431,.T.);
#879=EDGE_LOOP('',(#875,#876,#877,#878));
#880=FACE_BOUND('',#879,.T.);
#881=ADVANCED_FACE('F121',(#880),#869,.F.);
#882=CARTESIAN_POINT('',(-750.,-375.,253.111113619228));
#883=DIRECTION('',(0.,1.,0.));
#884=DIRECTION('',(0.,0.,1.));
#885=AXIS2_PLACEMENT_3D('',#882,#883,#884);
#886=PLANE('',#885);
#887=DIRECTION('',(0.,0.,-1.));
#888=VECTOR('',#887,1.);
#889=CARTESIAN_POINT('',(-300.,-375.,253.120113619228));
#890=LINE('',#889,#888);
#891=EDGE_CURVE('E56',#830,#416,#890,.T.);
#892=ORIENTED_EDGE('',*,*,#891,.T.);
#893=ORIENTED_EDGE('',*,*,#417,.T.);
#894=ORIENTED_EDGE('',*,*,#387,.F.);
#895=ORIENTED_EDGE('',*,*,#845,.F.);
#896=EDGE_LOOP('',(#892,#893,#894,#895));
#897=FACE_BOUND('',#896,.T.);
#898=ADVANCED_FACE('F37',(#897),#886,.F.);
#899=CARTESIAN_POINT('',(-300.,375.,253.120113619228));
#900=DIRECTION('',(-1.,0.,0.));
#901=DIRECTION('',(0.,-1.,0.));
#902=AXIS2_PLACEMENT_3D('',#899,#900,#901);
#903=PLANE('',#902);
#904=ORIENTED_EDGE('',*,*,#833,.T.);
#905=ORIENTED_EDGE('',*,*,#874,.T.);
#906=ORIENTED_EDGE('',*,*,#425,.F.);
#907=ORIENTED_EDGE('',*,*,#891,.F.);
#908=EDGE_LOOP('',(#904,#905,#906,#907));
#909=FACE_BOUND('',#908,.T.);
#910=ADVANCED_FACE('F145',(#909),#903,.T.);
#911=CLOSED_SHELL('',(#405,#436,#864,#881,#898,#910));
#912=MANIFOLD_SOLID_BREP('B2',#911);
#913=ADVANCED_BREP_SHAPE_REPRESENTATION('',(#18,#912),#14);
#914=SHAPE_DEFINITION_REPRESENTATION(#9,#913);
ENDSEC;
END-ISO-10303-21;
